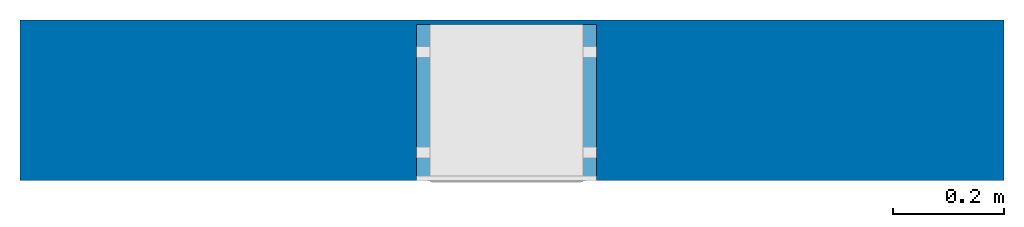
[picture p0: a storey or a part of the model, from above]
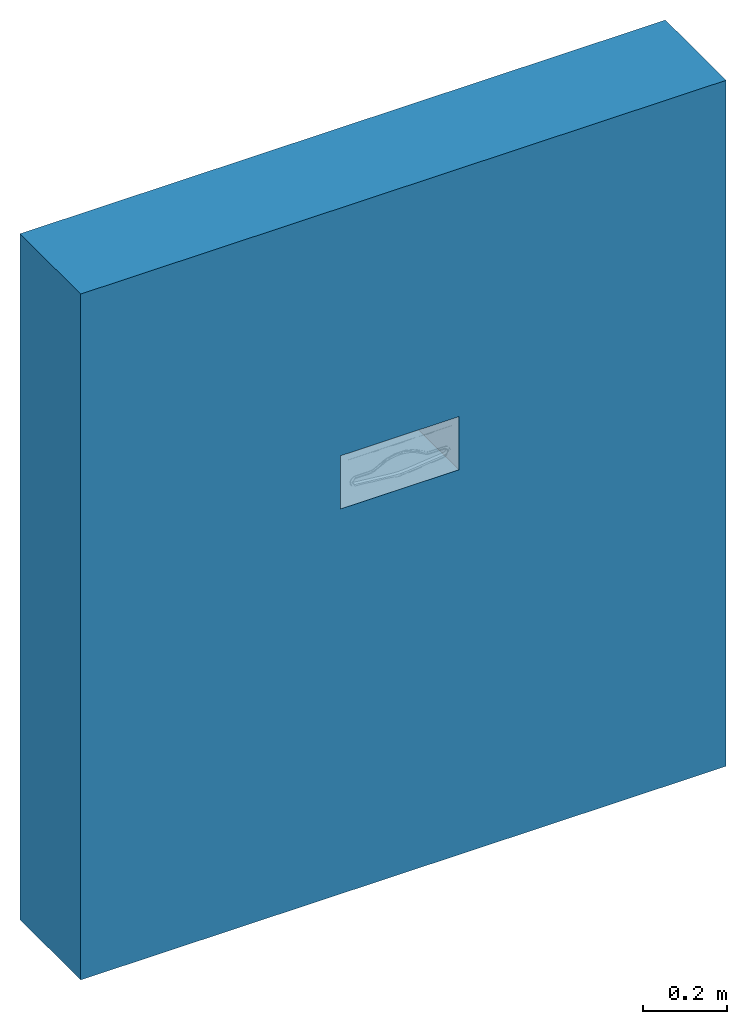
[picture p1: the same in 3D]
Properties of the parts of a building model (IFC2X3)

# File
Description: ViewDefinition [CoordinationView]
File name: Project Number
Time: 2018-10-31T13:59:14
Written by: The EXPRESS Data Manager Version 5.02.0100.07 : 28 Aug 2013
Made in: 20140606_1530(x64) - Exporter 2015.0.2014.0606 - Default UI
Comment: STEP Physical File produced by: The EXPRESS Data Manager Version 5.02.0100.07 : 28 Aug 2013 * Module: EDMstepFileFactory/EDMstandAlone * Creation date: Wed Oct 31 13:59:14 2018 * Host: SarahSams-HP * Database: C:\Users\SARAHS~1\AppData\Local\Temp\{CDA3613D-CD5A-4BD8-A62A-934CA04C59A4}\ifc * Database version: 5507 * Database creation date: Wed Oct 31 13:59:12 2018 * Schema: IFC2X3 * Model: DataRepository.ifc * Model creation date: Wed Oct 31 13:59:13 2018 * Header model: DataRepository.ifc_HeaderModel * Header model creation date: Wed Oct 31 13:59:13 2018 * EDMuser: sdai-user * EDMgroup: sdai-group * License ID and type: 5605 : Permanent license. Expiry date: * EDMstepFileFactory options: 020000

# IfcProject, Project Number
LongName: Project Name; Phase: Project Status

# IfcSite, Default
RefLatitude: 51, 30, 0, 549316; RefLongitude: 0, -7, -34, -450321; RefElevation: 0 mm
Other - Category: Project Information; Client Name: Owner; Project Address: Enter address here; Project Issue Date: Issue Date; Project Name: Project Name; Project Number: Project Number; Project Status: Project Status

# IfcBuilding
Pset_BuildingCommon - NumberOfStoreys: 1
Other - Category: Project Information; Client Name: Owner; Project Address: Enter address here; Project Issue Date: Issue Date; Project Name: Project Name; Project Number: Project Number; Project Status: Project Status

# IfcBuildingStorey, Level 0
LongName: Level 0; Elevation: 0 mm
Other - Category: Levels; Family Name: Level; Family: Level: Circle Head - Project Datum; Family and Type: Level: Circle Head - Project Datum; Type: Level: Circle Head - Project Datum; Type Id: Level: Circle Head - Project Datum
Identity Data - Type Name: Circle Head - Project Datum; Structural: no; Building Story: yes; Name: Level 0
Graphics - Color: 0; Line Pattern: Centre; Line Weight: 1; Symbol: Anno_Level_Head_Circle: Standard; Symbol at End 1 Default: yes; Symbol at End 2 Default: no
Constraints - Elevation: 0 mm; Elevation Base: Project Base Point
Dimensions - Computation Height: 0 mm

# IfcBuildingElementProxy: Recessed Spring Towel Dispenser, Duten_PprTwlDpnsrs_E050:Recessed Spring Towel Dispenser:260820
In: Level 0
Classification: E2020200 Furniture & Accessories (Uniformat); Material: Duten_Metal_BrushedStainlessSteel
Pset_BuildingElementProxyCommon - Reference: n/a
Pset_ManufacturerTypeInformation - ModelReference: Recessed Spring Towel Dispenser; Manufacturer: Duten
Constraints - Level: Level: Level 0; Elevation: 1200 mm; Host: Basic Wall : Wall-Ext_102Bwk-75Ins-100LBlk-12P; Default Elevation: 1200 mm
Dimensions - Area: 0.220373 m2; Volume: 0.00843483 m3
Other - Category: Generic Models; Family: Duten_PprTwlDpnsrs_E050: Recessed Spring Towel Dispenser; Family and Type: Duten_PprTwlDpnsrs_E050: Recessed Spring Towel Dispenser; Schedule Level: Level: Level 0; Type: Duten_PprTwlDpnsrs_E050: Recessed Spring Towel Dispenser; Type Id: Duten_PprTwlDpnsrs_E050: Recessed Spring Towel Dispenser; AccessibilityPerformance: n/a; AssetIdentifier: n/a; AssetType: Moveable; BarCode: n/a; CodePerformance: CE; Color: Defined by Finish; Constituents: Folded Stainless Steel Body and Refill Flap; DurationUnit: Years; ExpectedLife: 10; Family Name: Duten_PprTwlDpnsrs_E050; Features: Folded towel dispenser to be built into the partition, or on a worktop. Recessed, can be installed vertically or horizontally. 250-300 Capacity.; Finish: Brushed Stainless Steel; Grade: n/a; InstallationDate: 1900-12-31T23:59:59; Material: Stainless Steel AISI 304; ModelNumber: E050; ModelReference: Recessed Spring Towel Dispenser; Name: PaperTowelDispensers_E050_Duten; ReplacementCost: 0; SerialNumber: n/a; Shape: Rectangular; Size: (H) 155mm x (L) 285.7mm x (W) 326mm; SustainabilityPerformance: n/a; TagNumber: n/a; WarrantyDescription: n/a; WarrantyDurationLabor: 10; WarrantyDurationParts: 10; WarrantyDurationUnit: Years; WarrantyGuarantorLabor: contact@duten.fr; WarrantyGuarantorParts: contact@duten.fr; WarrantyStartDate: 1900-12-31T23:59:59
Phasing - Phase Created: New Construction
General - Author: Diane Butterworth Ltd; ManufacturerName: Duten; ManufacturerURL: http://www.duten.fr/; NBSDescription: Paper Towel Dispensers; NBSReference: 45-35-72/344; ProductInformation: http://www.duten.fr/?post_type=produits&p=2365&ca=distributeur-essuie-mains-inox; Revision: n/a; Uniclass2015Code: Pr_40_70_22_62; Uniclass2015Title: Paper Towel Dispensers; Uniclass2015Version: Pr-Products v1.10
Identity Data - Assembly Code: E2020200; Assembly Description: Furniture & Accessories; Cost: 0; Description: Recessed Spring Towel Dispenser; Keynote: Pr_40_70_22_62; Manufacturer: Duten; Model: E050; Type Comments: Recessed Spring Towel Dispenser; Type Name: Recessed Spring Towel Dispenser; URL: http://www.duten.fr/

# IfcOpeningElement: Recess, Basic Wall:Wall-Ext_102Bwk-75Ins-100LBlk-12P:260800
In: Level 0
Constraints - Elevation: 1200 mm; Host: Basic Wall : Wall-Ext_102Bwk-75Ins-100LBlk-12P; Level: Level: Level 0; Default Elevation: 1200 mm
Dimensions - Area: 0.220373 m2; Volume: 0.00843483 m3
Other - Category: Generic Models; Family: Duten_PprTwlDpnsrs_E050: Recessed Spring Towel Dispenser; Family and Type: Duten_PprTwlDpnsrs_E050: Recessed Spring Towel Dispenser; Schedule Level: Level: Level 0; Type: Duten_PprTwlDpnsrs_E050: Recessed Spring Towel Dispenser; Type Id: Duten_PprTwlDpnsrs_E050: Recessed Spring Towel Dispenser; AccessibilityPerformance: n/a; AssetIdentifier: n/a; AssetType: Moveable; BarCode: n/a; CodePerformance: CE; Color: Defined by Finish; Constituents: Folded Stainless Steel Body and Refill Flap; DurationUnit: Years; ExpectedLife: 10; Family Name: Duten_PprTwlDpnsrs_E050; Features: Folded towel dispenser to be built into the partition, or on a worktop. Recessed, can be installed vertically or horizontally. 250-300 Capacity.; Finish: Brushed Stainless Steel; Grade: n/a; InstallationDate: 1900-12-31T23:59:59; Material: Stainless Steel AISI 304; ModelNumber: E050; ModelReference: Recessed Spring Towel Dispenser; Name: PaperTowelDispensers_E050_Duten; ReplacementCost: 0; SerialNumber: n/a; Shape: Rectangular; Size: (H) 155mm x (L) 285.7mm x (W) 326mm; SustainabilityPerformance: n/a; TagNumber: n/a; WarrantyDescription: n/a; WarrantyDurationLabor: 10; WarrantyDurationParts: 10; WarrantyDurationUnit: Years; WarrantyGuarantorLabor: contact@duten.fr; WarrantyGuarantorParts: contact@duten.fr; WarrantyStartDate: 1900-12-31T23:59:59
Phasing - Phase Created: New Construction
General - Author: Diane Butterworth Ltd; ManufacturerName: Duten; ManufacturerURL: http://www.duten.fr/; NBSDescription: Paper Towel Dispensers; NBSReference: 45-35-72/344; ProductInformation: http://www.duten.fr/?post_type=produits&p=2365&ca=distributeur-essuie-mains-inox; Revision: n/a; Uniclass2015Code: Pr_40_70_22_62; Uniclass2015Title: Paper Towel Dispensers; Uniclass2015Version: Pr-Products v1.10
Identity Data - Assembly Code: E2020200; Assembly Description: Furniture & Accessories; Cost: 0; Description: Recessed Spring Towel Dispenser; Keynote: Pr_40_70_22_62; Manufacturer: Duten; Model: E050; Type Comments: Recessed Spring Towel Dispenser; Type Name: Recessed Spring Towel Dispenser; URL: http://www.duten.fr/

# IfcWallStandardCase: Basic Wall:Wall-Ext_102Bwk-75Ins-100LBlk-12P, Basic Wall:Wall-Ext_102Bwk-75Ins-100LBlk-12P:260800
In: Level 0
Type - PredefinedType: STANDARD; Material: Brick, Common 102.5 mm, Fiberglass Batt 75 mm, Concrete Masonry Units _Low Density 100 mm, Plaster 12.5 mm
Type - Analytical Properties - Absorptance: 0.7; Heat Transfer Coefficient (U): 0.235926; Roughness: 3; Thermal mass: 300303; Thermal Resistance (R): 4.23862
Type - Construction - Function: Exterior; Width: 290 mm; Wrapping at Inserts: Both
Type - Graphics - Coarse Scale Fill Color: 12632256; Coarse Scale Fill Pattern: Solid fill
Type - Identity Data - Keynote: F10; Type Name: Wall-Ext_102Bwk-75Ins-100LBlk-12P
Type - Materials and Finishes - Structural Material: Concrete Masonry Units _Low Density
Type - Other - Category: Walls; Family Name: Basic Wall
Constraints - Base Constraint: Level: Level 0; Base Extension Distance: 0 mm; Base is Attached: no; Base Offset: 0 mm; Location Line: Wall Centerline; Related to Mass: no; Room Bounding: yes; Top Extension Distance: 0 mm; Top is Attached: no; Top Offset: 0 mm; Unconnected Height: 2000 mm
Dimensions - Area: 3.56 m2; Length: 1780 mm; Volume: 1.01815 m3
Other - Family: Basic Wall: Wall-Ext_102Bwk-75Ins-100LBlk-12P; Family and Type: Basic Wall: Wall-Ext_102Bwk-75Ins-100LBlk-12P; Type: Basic Wall: Wall-Ext_102Bwk-75Ins-100LBlk-12P; Type Id: Basic Wall: Wall-Ext_102Bwk-75Ins-100LBlk-12P
Phasing - Phase Created: New Construction
Structural - Enable Analytical Model: no; Structural: no; Structural Usage: Non-bearing
Pset_WallCommon - Reference: Wall-Ext_102Bwk-75Ins-100LBlk-12P; LoadBearing: no; ExtendToStructure: no; IsExternal: yes; ThermalTransmittance: 0.235926 kg/K/s3
